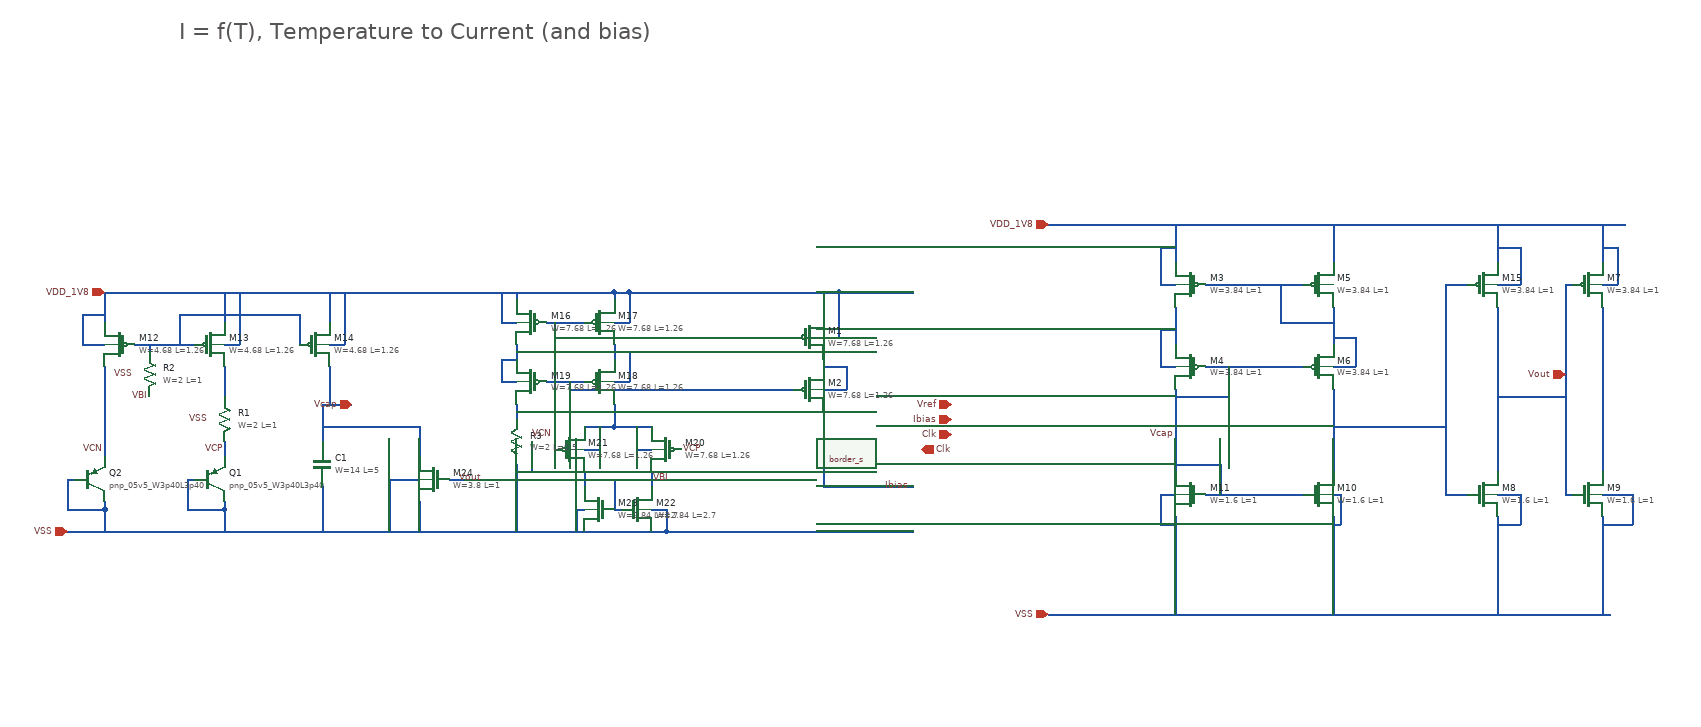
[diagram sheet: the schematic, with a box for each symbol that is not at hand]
v {xschem version=3.4.4 file_version=1.2
}
G {}
K {}
V {}
S {}
E {}
T {I = f(T), Temperature to Current (and bias)} 310 -1040 0 0 1 1 {}
N 210 -680 210 -640 {
lab=VDD_1V8}
N 370 -680 370 -640 {
lab=VDD_1V8}
N 370 -580 370 -540 {
lab=#net1}
N 370 -480 370 -460 {
lab=VCP}
N 320 -430 330 -430 {
lab=VSS}
N 320 -430 320 -390 {
lab=VSS}
N 320 -390 370 -390 {
lab=VSS}
N 370 -400 370 -390 {
lab=VSS}
N 160 -430 170 -430 {
lab=VSS}
N 160 -430 160 -390 {
lab=VSS}
N 160 -390 210 -390 {
lab=VSS}
N 210 -400 210 -390 {
lab=VSS}
N 210 -580 210 -460 {
lab=VCN}
N 210 -680 890 -680 {
lab=VDD_1V8}
N 250 -610 330 -610 {
lab=#net2}
N 310 -650 310 -610 {
lab=#net2}
N 510 -680 510 -640 {
lab=VDD_1V8}
N 310 -650 470 -650 {
lab=#net2}
N 470 -650 470 -610 {
lab=#net2}
N 510 -580 510 -530 {
lab=Vcap}
N 760 -680 760 -670 {
lab=VDD_1V8}
N 890 -680 890 -670 {
lab=VDD_1V8}
N 800 -640 850 -640 {
lab=#net3}
N 810 -640 810 -610 {
lab=#net3}
N 800 -560 850 -560 {
lab=#net4}
N 810 -560 810 -520 {
lab=#net4}
N 760 -520 810 -520 {
lab=#net4}
N 760 -610 760 -590 {
lab=#net3}
N 760 -600 810 -600 {
lab=#net3}
N 810 -610 810 -600 {
lab=#net3}
N 760 -530 760 -510 {
lab=#net4}
N 890 -610 890 -590 {
lab=#net5}
N 890 -530 890 -500 {
lab=#net6}
N 850 -500 890 -500 {
lab=#net6}
N 890 -500 940 -500 {
lab=#net6}
N 850 -440 850 -420 {
lab=#net7}
N 940 -440 940 -420 {
lab=VBI}
N 890 -390 900 -390 {
lab=VBI}
N 890 -430 890 -390 {
lab=VBI}
N 890 -430 940 -430 {
lab=VBI}
N 850 -360 940 -360 {
lab=VSS}
N 160 -360 850 -360 {
lab=VSS}
N 210 -390 210 -360 {
lab=VSS}
N 370 -390 370 -360 {
lab=VSS}
N 760 -450 760 -360 {
lab=VSS}
N 780 -480 780 -440 {
lab=VSS}
N 760 -440 780 -440 {
lab=VSS}
N 810 -490 810 -470 {
lab=VCN}
N 940 -390 960 -390 {
lab=VSS}
N 960 -390 960 -360 {
lab=VSS}
N 940 -360 960 -360 {
lab=VSS}
N 840 -390 850 -390 {
lab=VSS}
N 840 -390 840 -360 {
lab=VSS}
N 890 -560 910 -560 {
lab=#net5}
N 910 -600 910 -560 {
lab=#net5}
N 890 -600 910 -600 {
lab=#net5}
N 890 -640 910 -640 {
lab=VDD_1V8}
N 910 -680 910 -640 {
lab=VDD_1V8}
N 890 -680 910 -680 {
lab=VDD_1V8}
N 740 -560 760 -560 {
lab=#net3}
N 740 -590 740 -560 {
lab=#net3}
N 740 -590 760 -590 {
lab=#net3}
N 740 -640 760 -640 {
lab=VDD_1V8}
N 740 -680 740 -640 {
lab=VDD_1V8}
N 850 -470 870 -470 {
lab=#net6}
N 870 -500 870 -470 {
lab=#net6}
N 920 -470 940 -470 {
lab=#net6}
N 920 -500 920 -470 {
lab=#net6}
N 510 -610 530 -610 {
lab=VDD_1V8}
N 530 -680 530 -610 {
lab=VDD_1V8}
N 370 -610 390 -610 {
lab=VDD_1V8}
N 390 -680 390 -610 {
lab=VDD_1V8}
N 180 -610 210 -610 {
lab=VDD_1V8}
N 180 -650 180 -610 {
lab=VDD_1V8}
N 180 -650 210 -650 {
lab=VDD_1V8}
N 500 -530 500 -480 {
lab=Vcap}
N 500 -420 500 -370 {
lab=VSS}
N 670 -430 690 -430 {
lab=Vcap}
N 590 -430 630 -430 {
lab=VSS}
N 630 -500 630 -460 {
lab=Vcap}
N 500 -530 540 -530 {
lab=Vcap}
N 590 -430 590 -370 {
lab=VSS}
N 630 -400 630 -370 {
lab=VSS}
N 590 -370 590 -360 {
lab=VSS}
N 630 -370 630 -360 {
lab=VSS}
N 500 -370 500 -360 {
lab=VSS}
N 270 -610 270 -600 {
lab=#net2}
N 500 -500 630 -500 {
lab=Vcap}
N 910 -680 1040 -680 {
lab=VDD_1V8}
N 960 -360 1090 -360 {
lab=VSS}
N 810 -620 1130 -620 {
lab=#net3}
N 830 -560 830 -550 {
lab=#net4}
N 830 -550 1130 -550 {
lab=#net4}
N 1170 -590 1170 -580 {
lab=#net8}
N 1170 -550 1200 -550 {
lab=#net8}
N 1200 -580 1200 -550 {
lab=#net8}
N 1170 -580 1200 -580 {
lab=#net8}
N 1170 -620 1190 -620 {
lab=VDD_1V8}
N 1190 -680 1190 -620 {
lab=VDD_1V8}
N 1040 -680 1190 -680 {
lab=VDD_1V8}
N 1170 -680 1170 -650 {
lab=VDD_1V8}
N 1170 -520 1170 -460 {
lab=Ibias}
N 1190 -680 1290 -680 {
lab=VDD_1V8}
N 1090 -360 1290 -360 {
lab=VSS}
N 1170 -460 1170 -420 {
lab=Ibias}
N 1170 -420 1290 -420 {
lab=Ibias}
N 1470 -770 2220 -770 {
lab=VDD_1V8}
N 1470 -250 2220 -250 {
lab=VSS}
N 1850 -380 1850 -250 {
lab=VSS}
N 2220 -770 2240 -770 {
lab=VDD_1V8}
N 1620 -410 1640 -410 {
lab=VSS}
N 1620 -410 1620 -370 {
lab=VSS}
N 1620 -370 1640 -370 {
lab=VSS}
N 1850 -410 1860 -410 {
lab=VSS}
N 1860 -410 1860 -370 {
lab=VSS}
N 1850 -370 1860 -370 {
lab=VSS}
N 1620 -690 1640 -690 {
lab=VDD_1V8}
N 1620 -740 1620 -690 {
lab=VDD_1V8}
N 1620 -740 1640 -740 {
lab=VDD_1V8}
N 1620 -580 1640 -580 {
lab=#net9}
N 1620 -630 1620 -580 {
lab=#net9}
N 1620 -630 1640 -630 {
lab=#net9}
N 1640 -770 1640 -720 {
lab=VDD_1V8}
N 1640 -660 1640 -610 {
lab=#net9}
N 1850 -660 1850 -610 {
lab=#net10}
N 1850 -770 1850 -720 {
lab=VDD_1V8}
N 1680 -690 1810 -690 {
lab=#net10}
N 1780 -690 1780 -640 {
lab=#net10}
N 1780 -640 1850 -640 {
lab=#net10}
N 1680 -580 1810 -580 {
lab=Vcap}
N 1850 -550 1850 -440 {
lab=#net11}
N 1640 -550 1640 -440 {
lab=Vcap}
N 1640 -380 1640 -250 {
lab=VSS}
N 1680 -410 1810 -410 {
lab=Vcap}
N 1700 -450 1700 -410 {
lab=Vcap}
N 1640 -450 1700 -450 {
lab=Vcap}
N 1710 -580 1710 -540 {
lab=Vcap}
N 1640 -540 1710 -540 {
lab=Vcap}
N 1850 -580 1880 -580 {
lab=#net10}
N 1880 -620 1880 -580 {
lab=#net10}
N 1850 -620 1880 -620 {
lab=#net10}
N 2070 -770 2070 -720 {
lab=VDD_1V8}
N 2210 -770 2210 -720 {
lab=VDD_1V8}
N 2070 -660 2070 -440 {
lab=Vout}
N 2210 -660 2210 -440 {
lab=#net12}
N 2070 -690 2100 -690 {
lab=VDD_1V8}
N 2100 -740 2100 -690 {
lab=VDD_1V8}
N 2070 -740 2100 -740 {
lab=VDD_1V8}
N 2210 -690 2230 -690 {
lab=VDD_1V8}
N 2230 -740 2230 -690 {
lab=VDD_1V8}
N 2210 -740 2230 -740 {
lab=VDD_1V8}
N 2160 -690 2170 -690 {
lab=Vout}
N 2160 -690 2160 -410 {
lab=Vout}
N 2160 -410 2170 -410 {
lab=Vout}
N 2210 -380 2210 -250 {
lab=VSS}
N 2070 -380 2070 -250 {
lab=VSS}
N 2070 -410 2100 -410 {
lab=VSS}
N 2100 -410 2100 -370 {
lab=VSS}
N 2070 -370 2100 -370 {
lab=VSS}
N 2210 -410 2250 -410 {
lab=VSS}
N 2250 -410 2250 -370 {
lab=VSS}
N 2210 -370 2250 -370 {
lab=VSS}
N 2070 -540 2160 -540 {
lab=Vout}
N 2000 -690 2030 -690 {
lab=#net11}
N 2000 -690 2000 -410 {
lab=#net11}
N 2000 -410 2030 -410 {
lab=#net11}
N 1850 -500 2000 -500 {
lab=#net11}
C {cborder/border_s.sym} 1250 -170 0 0 {
user="wulff"
company="wulff"}
C {devices/ipin.sym} 210 -680 0 0 {name=p1 lab=VDD_1V8}
C {devices/ipin.sym} 160 -360 0 0 {name=p2 lab=VSS}
C {devices/lab_wire.sym} 210 -470 0 0 {name=p3 sig_type=std_logic lab=VCN}
C {sky130_fd_pr/pnp_05v5.sym} 350 -430 0 0 {name=Q1
model=pnp_05v5_W3p40L3p40
m=8
spiceprefix=X
}
C {sky130_fd_pr/res_high_po.sym} 370 -510 0 0 {name=R1
W=2
L=1
model=res_high_po
mult=0.25}
C {sky130_fd_pr/pnp_05v5.sym} 190 -430 0 0 {name=Q2
model=pnp_05v5_W3p40L3p40
m=8
spiceprefix=X
}
C {sky130_fd_pr/pfet_01v8.sym} 230 -610 0 1 {name=M12
L=1.26
W=4.68
nf=1
mult=1
ad="'int((nf+1)/2) * W/nf * 0.29'"
pd="'2*int((nf+1)/2) * (W/nf + 0.29)'"
as="'int((nf+2)/2) * W/nf * 0.29'"
ps="'2*int((nf+2)/2) * (W/nf + 0.29)'"
nrd="'0.29 / W'" nrs="'0.29 / W'"
sa=0 sb=0 sd=0
model=pfet_01v8
spiceprefix=X
}
C {sky130_fd_pr/pfet_01v8.sym} 350 -610 0 0 {name=M13
L=1.26
W=4.68
nf=1
mult=1
ad="'int((nf+1)/2) * W/nf * 0.29'"
pd="'2*int((nf+1)/2) * (W/nf + 0.29)'"
as="'int((nf+2)/2) * W/nf * 0.29'"
ps="'2*int((nf+2)/2) * (W/nf + 0.29)'"
nrd="'0.29 / W'" nrs="'0.29 / W'"
sa=0 sb=0 sd=0
model=pfet_01v8
spiceprefix=X
}
C {sky130_fd_pr/pfet_01v8.sym} 490 -610 0 0 {name=M14
L=1.26
W=4.68
nf=1
mult=1
ad="'int((nf+1)/2) * W/nf * 0.29'"
pd="'2*int((nf+1)/2) * (W/nf + 0.29)'"
as="'int((nf+2)/2) * W/nf * 0.29'"
ps="'2*int((nf+2)/2) * (W/nf + 0.29)'"
nrd="'0.29 / W'" nrs="'0.29 / W'"
sa=0 sb=0 sd=0
model=pfet_01v8
spiceprefix=X
}
C {sky130_fd_pr/pfet_01v8.sym} 780 -640 0 1 {name=M16
L=1.26
W=7.68
nf=1
mult=1
ad="'int((nf+1)/2) * W/nf * 0.29'"
pd="'2*int((nf+1)/2) * (W/nf + 0.29)'"
as="'int((nf+2)/2) * W/nf * 0.29'"
ps="'2*int((nf+2)/2) * (W/nf + 0.29)'"
nrd="'0.29 / W'" nrs="'0.29 / W'"
sa=0 sb=0 sd=0
model=pfet_01v8
spiceprefix=X
}
C {sky130_fd_pr/pfet_01v8.sym} 870 -640 0 0 {name=M17
L=1.26
W=7.68
nf=1
mult=1
ad="'int((nf+1)/2) * W/nf * 0.29'"
pd="'2*int((nf+1)/2) * (W/nf + 0.29)'"
as="'int((nf+2)/2) * W/nf * 0.29'"
ps="'2*int((nf+2)/2) * (W/nf + 0.29)'"
nrd="'0.29 / W'" nrs="'0.29 / W'"
sa=0 sb=0 sd=0
model=pfet_01v8
spiceprefix=X
}
C {sky130_fd_pr/pfet_01v8.sym} 870 -560 0 0 {name=M18
L=1.26
W=7.68
nf=1
mult=1
ad="'int((nf+1)/2) * W/nf * 0.29'"
pd="'2*int((nf+1)/2) * (W/nf + 0.29)'"
as="'int((nf+2)/2) * W/nf * 0.29'"
ps="'2*int((nf+2)/2) * (W/nf + 0.29)'"
nrd="'0.29 / W'" nrs="'0.29 / W'"
sa=0 sb=0 sd=0
model=pfet_01v8
spiceprefix=X
}
C {sky130_fd_pr/pfet_01v8.sym} 780 -560 0 1 {name=M19
L=1.26
W=7.68
nf=1
mult=1
ad="'int((nf+1)/2) * W/nf * 0.29'"
pd="'2*int((nf+1)/2) * (W/nf + 0.29)'"
as="'int((nf+2)/2) * W/nf * 0.29'"
ps="'2*int((nf+2)/2) * (W/nf + 0.29)'"
nrd="'0.29 / W'" nrs="'0.29 / W'"
sa=0 sb=0 sd=0
model=pfet_01v8
spiceprefix=X
}
C {sky130_fd_pr/pfet_01v8.sym} 960 -470 0 1 {name=M20
L=1.26
W=7.68
nf=1
mult=1
ad="'int((nf+1)/2) * W/nf * 0.29'"
pd="'2*int((nf+1)/2) * (W/nf + 0.29)'"
as="'int((nf+2)/2) * W/nf * 0.29'"
ps="'2*int((nf+2)/2) * (W/nf + 0.29)'"
nrd="'0.29 / W'" nrs="'0.29 / W'"
sa=0 sb=0 sd=0
model=pfet_01v8
spiceprefix=X
}
C {sky130_fd_pr/pfet_01v8.sym} 830 -470 0 0 {name=M21
L=1.26
W=7.68
nf=1
mult=1
ad="'int((nf+1)/2) * W/nf * 0.29'"
pd="'2*int((nf+1)/2) * (W/nf + 0.29)'"
as="'int((nf+2)/2) * W/nf * 0.29'"
ps="'2*int((nf+2)/2) * (W/nf + 0.29)'"
nrd="'0.29 / W'" nrs="'0.29 / W'"
sa=0 sb=0 sd=0
model=pfet_01v8
spiceprefix=X
}
C {sky130_fd_pr/nfet_01v8.sym} 920 -390 0 0 {name=M22
L=2.7
W=2.84
nf=1
mult=1
ad="'int((nf+1)/2) * W/nf * 0.29'"
pd="'2*int((nf+1)/2) * (W/nf + 0.29)'"
as="'int((nf+2)/2) * W/nf * 0.29'"
ps="'2*int((nf+2)/2) * (W/nf + 0.29)'"
nrd="'0.29 / W'" nrs="'0.29 / W'"
sa=0 sb=0 sd=0
model=nfet_01v8
spiceprefix=X
}
C {sky130_fd_pr/nfet_01v8.sym} 870 -390 0 1 {name=M23
L=2.7
W=2.84
nf=1
mult=1
ad="'int((nf+1)/2) * W/nf * 0.29'"
pd="'2*int((nf+1)/2) * (W/nf + 0.29)'"
as="'int((nf+2)/2) * W/nf * 0.29'"
ps="'2*int((nf+2)/2) * (W/nf + 0.29)'"
nrd="'0.29 / W'" nrs="'0.29 / W'"
sa=0 sb=0 sd=0
model=nfet_01v8
spiceprefix=X
}
C {sky130_fd_pr/res_high_po.sym} 760 -480 0 1 {name=R3
W=2
L=0.5
model=res_high_po
mult=0.05}
C {devices/lab_wire.sym} 370 -470 0 0 {name=p9 sig_type=std_logic lab=VCP}
C {devices/lab_wire.sym} 810 -490 0 0 {name=p10 sig_type=std_logic lab=VCN}
C {devices/lab_wire.sym} 980 -470 0 1 {name=p12 sig_type=std_logic lab=VCP}
C {devices/lab_wire.sym} 350 -510 0 0 {name=p8 sig_type=std_logic lab=VSS}
C {sky130_fd_pr/cap_mim_m3_1.sym} 500 -450 0 1 {name=C1 model=cap_mim_m3_1 W=14 L=5 MF=25 spiceprefix=X}
C {sky130_fd_pr/nfet_01v8.sym} 650 -430 0 1 {name=M24
L=1
W=3.8
nf=1
mult=1
ad="'int((nf+1)/2) * W/nf * 0.29'"
pd="'2*int((nf+1)/2) * (W/nf + 0.29)'"
as="'int((nf+2)/2) * W/nf * 0.29'"
ps="'2*int((nf+2)/2) * (W/nf + 0.29)'"
nrd="'0.29 / W'" nrs="'0.29 / W'"
sa=0 sb=0 sd=0
model=nfet_01v8
spiceprefix=X
}
C {devices/ipin.sym} 1300 -470 0 1 {name=p6 lab=Clk
}
C {devices/opin.sym} 540 -530 2 1 {name=p13 lab=Vcap
}
C {sky130_fd_pr/res_high_po.sym} 270 -570 0 0 {name=R2
W=2
L=1
model=res_high_po
mult=0.25}
C {devices/lab_wire.sym} 270 -540 0 0 {name=p4 sig_type=std_logic lab=VBI}
C {devices/lab_wire.sym} 250 -570 0 0 {name=p5 sig_type=std_logic lab=VSS}
C {devices/lab_wire.sym} 940 -430 0 1 {name=p7 sig_type=std_logic lab=VBI}
C {sky130_fd_pr/pfet_01v8.sym} 1150 -620 0 0 {name=M1
L=1.26
W=7.68
nf=1
mult=1
ad="'int((nf+1)/2) * W/nf * 0.29'"
pd="'2*int((nf+1)/2) * (W/nf + 0.29)'"
as="'int((nf+2)/2) * W/nf * 0.29'"
ps="'2*int((nf+2)/2) * (W/nf + 0.29)'"
nrd="'0.29 / W'" nrs="'0.29 / W'"
sa=0 sb=0 sd=0
model=pfet_01v8
spiceprefix=X
}
C {sky130_fd_pr/pfet_01v8.sym} 1150 -550 0 0 {name=M2
L=1.26
W=7.68
nf=1
mult=1
ad="'int((nf+1)/2) * W/nf * 0.29'"
pd="'2*int((nf+1)/2) * (W/nf + 0.29)'"
as="'int((nf+2)/2) * W/nf * 0.29'"
ps="'2*int((nf+2)/2) * (W/nf + 0.29)'"
nrd="'0.29 / W'" nrs="'0.29 / W'"
sa=0 sb=0 sd=0
model=pfet_01v8
spiceprefix=X
}
C {devices/ipin.sym} 1470 -770 0 0 {name=p11 lab=VDD_1V8}
C {devices/ipin.sym} 1470 -250 0 0 {name=p14 lab=VSS}
C {devices/ipin.sym} 1340 -530 0 0 {name=p16 lab=Vref}
C {devices/ipin.sym} 1340 -510 0 0 {name=p24 lab=Ibias}
C {sky130_fd_pr/pfet_01v8.sym} 1660 -690 0 1 {name=M3
L=1
W=3.84
nf=1
mult=1
ad="'int((nf+1)/2) * W/nf * 0.29'"
pd="'2*int((nf+1)/2) * (W/nf + 0.29)'"
as="'int((nf+2)/2) * W/nf * 0.29'"
ps="'2*int((nf+2)/2) * (W/nf + 0.29)'"
nrd="'0.29 / W'" nrs="'0.29 / W'"
sa=0 sb=0 sd=0
model=pfet_01v8
spiceprefix=X
}
C {sky130_fd_pr/nfet_01v8.sym} 1830 -410 0 0 {name=M10
L=1
W=1.6
nf=1
mult=1
ad="'int((nf+1)/2) * W/nf * 0.29'"
pd="'2*int((nf+1)/2) * (W/nf + 0.29)'"
as="'int((nf+2)/2) * W/nf * 0.29'"
ps="'2*int((nf+2)/2) * (W/nf + 0.29)'"
nrd="'0.29 / W'" nrs="'0.29 / W'"
sa=0 sb=0 sd=0
model=nfet_01v8
spiceprefix=X
}
C {sky130_fd_pr/nfet_01v8.sym} 1660 -410 0 1 {name=M11
L=1
W=1.6
nf=1
mult=1
ad="'int((nf+1)/2) * W/nf * 0.29'"
pd="'2*int((nf+1)/2) * (W/nf + 0.29)'"
as="'int((nf+2)/2) * W/nf * 0.29'"
ps="'2*int((nf+2)/2) * (W/nf + 0.29)'"
nrd="'0.29 / W'" nrs="'0.29 / W'"
sa=0 sb=0 sd=0
model=nfet_01v8
spiceprefix=X
}
C {devices/ipin.sym} 1340 -490 0 0 {name=p18 lab=Clk}
C {devices/lab_wire.sym} 1250 -420 0 1 {name=p17 sig_type=std_logic lab=Ibias}
C {sky130_fd_pr/pfet_01v8.sym} 1830 -690 0 0 {name=M5
L=1
W=3.84
nf=1
mult=1
ad="'int((nf+1)/2) * W/nf * 0.29'"
pd="'2*int((nf+1)/2) * (W/nf + 0.29)'"
as="'int((nf+2)/2) * W/nf * 0.29'"
ps="'2*int((nf+2)/2) * (W/nf + 0.29)'"
nrd="'0.29 / W'" nrs="'0.29 / W'"
sa=0 sb=0 sd=0
model=pfet_01v8
spiceprefix=X
}
C {sky130_fd_pr/pfet_01v8.sym} 2050 -690 0 0 {name=M15
L=1
W=3.84
nf=1
mult=1
ad="'int((nf+1)/2) * W/nf * 0.29'"
pd="'2*int((nf+1)/2) * (W/nf + 0.29)'"
as="'int((nf+2)/2) * W/nf * 0.29'"
ps="'2*int((nf+2)/2) * (W/nf + 0.29)'"
nrd="'0.29 / W'" nrs="'0.29 / W'"
sa=0 sb=0 sd=0
model=pfet_01v8
spiceprefix=X
}
C {devices/opin.sym} 2160 -570 2 1 {name=p15 lab=Vout
}
C {sky130_fd_pr/pfet_01v8.sym} 1660 -580 0 1 {name=M4
L=1
W=3.84
nf=1
mult=1
ad="'int((nf+1)/2) * W/nf * 0.29'"
pd="'2*int((nf+1)/2) * (W/nf + 0.29)'"
as="'int((nf+2)/2) * W/nf * 0.29'"
ps="'2*int((nf+2)/2) * (W/nf + 0.29)'"
nrd="'0.29 / W'" nrs="'0.29 / W'"
sa=0 sb=0 sd=0
model=pfet_01v8
spiceprefix=X
}
C {sky130_fd_pr/pfet_01v8.sym} 1830 -580 0 0 {name=M6
L=1
W=3.84
nf=1
mult=1
ad="'int((nf+1)/2) * W/nf * 0.29'"
pd="'2*int((nf+1)/2) * (W/nf + 0.29)'"
as="'int((nf+2)/2) * W/nf * 0.29'"
ps="'2*int((nf+2)/2) * (W/nf + 0.29)'"
nrd="'0.29 / W'" nrs="'0.29 / W'"
sa=0 sb=0 sd=0
model=pfet_01v8
spiceprefix=X
}
C {sky130_fd_pr/pfet_01v8.sym} 2190 -690 0 0 {name=M7
L=1
W=3.84
nf=1
mult=1
ad="'int((nf+1)/2) * W/nf * 0.29'"
pd="'2*int((nf+1)/2) * (W/nf + 0.29)'"
as="'int((nf+2)/2) * W/nf * 0.29'"
ps="'2*int((nf+2)/2) * (W/nf + 0.29)'"
nrd="'0.29 / W'" nrs="'0.29 / W'"
sa=0 sb=0 sd=0
model=pfet_01v8
spiceprefix=X
}
C {sky130_fd_pr/nfet_01v8.sym} 2050 -410 0 0 {name=M8
L=1
W=1.6
nf=1
mult=1
ad="'int((nf+1)/2) * W/nf * 0.29'"
pd="'2*int((nf+1)/2) * (W/nf + 0.29)'"
as="'int((nf+2)/2) * W/nf * 0.29'"
ps="'2*int((nf+2)/2) * (W/nf + 0.29)'"
nrd="'0.29 / W'" nrs="'0.29 / W'"
sa=0 sb=0 sd=0
model=nfet_01v8
spiceprefix=X
}
C {sky130_fd_pr/nfet_01v8.sym} 2190 -410 0 0 {name=M9
L=1
W=1.6
nf=1
mult=1
ad="'int((nf+1)/2) * W/nf * 0.29'"
pd="'2*int((nf+1)/2) * (W/nf + 0.29)'"
as="'int((nf+2)/2) * W/nf * 0.29'"
ps="'2*int((nf+2)/2) * (W/nf + 0.29)'"
nrd="'0.29 / W'" nrs="'0.29 / W'"
sa=0 sb=0 sd=0
model=nfet_01v8
spiceprefix=X
}
C {devices/lab_wire.sym} 1640 -490 0 0 {name=p19 sig_type=std_logic lab=Vcap}
C {devices/lab_wire.sym} 680 -430 0 1 {name=p20 sig_type=std_logic lab=Vout}
